VERSION 5.7 ;
BUSBITCHARS "[]" ;
DIVIDERCHAR "/" ;
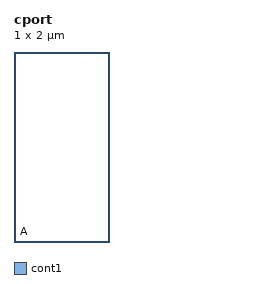
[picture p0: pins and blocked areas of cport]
MACRO cport
  CLASS CORE ;
  ORIGIN 0 0 ;
  SIZE 1 BY 2 ;
  PIN A
    DIRECTION INPUT ;
    PORT
      LAYER cont1 ;
        RECT 0.1 0.1 0.12 0.12 ;
    END
  END A
END cport
END LIBRARY
